VERSION 5.7 ;
  NOWIREEXTENSIONATPIN ON ;
  DIVIDERCHAR "/" ;
  BUSBITCHARS "[]" ;
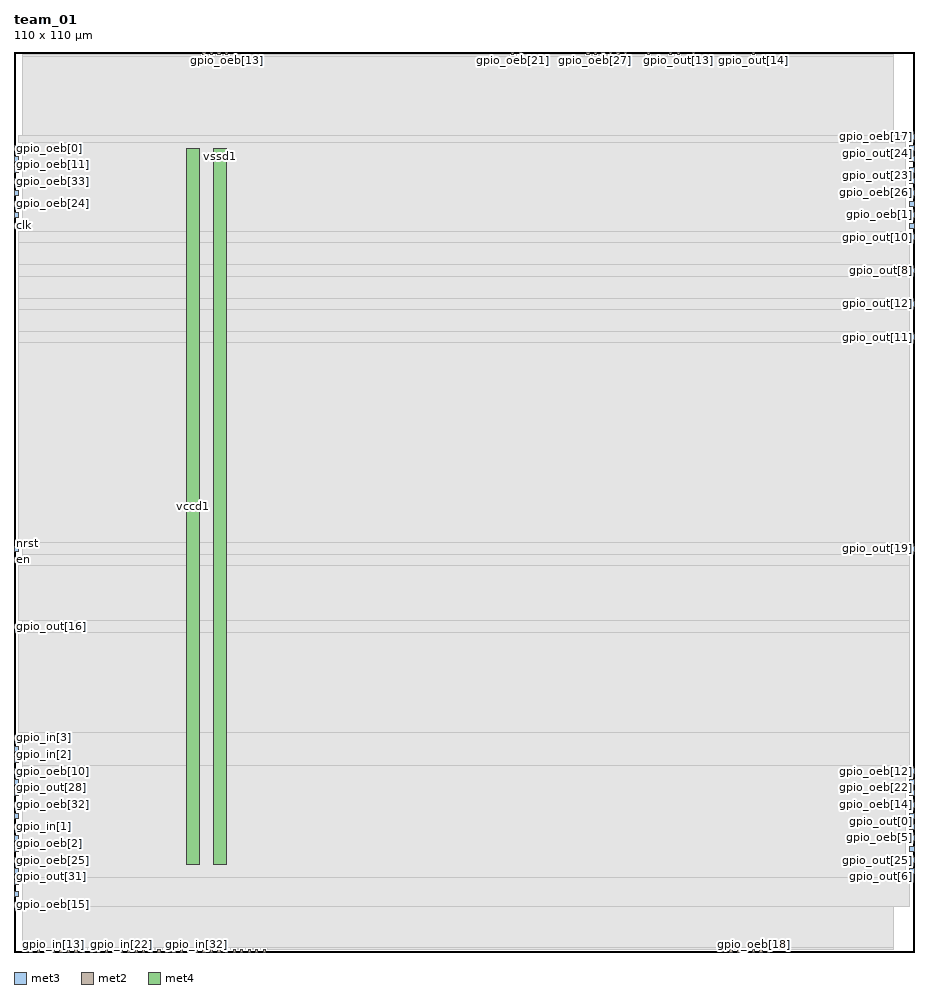
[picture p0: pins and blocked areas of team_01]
MACRO team_01
  CLASS BLOCK ;
  FOREIGN team_01 ;
  ORIGIN 0.000 0.000 ;
  SIZE 110.000 BY 110.000 ;
  PIN clk
    DIRECTION INPUT ;
    USE SIGNAL ;
    ANTENNAGATEAREA 1.286700 ;
    ANTENNADIFFAREA 0.434700 ;
    PORT
      LAYER met3 ;
        RECT 0.000 88.440 0.600 89.040 ;
    END
  END clk
  PIN en
    DIRECTION INPUT ;
    USE SIGNAL ;
    ANTENNAGATEAREA 0.647700 ;
    ANTENNADIFFAREA 0.434700 ;
    PORT
      LAYER met3 ;
        RECT 0.000 47.640 0.600 48.240 ;
    END
  END en
  PIN gpio_in[0]
    DIRECTION INPUT ;
    USE SIGNAL ;
    ANTENNAGATEAREA 0.647700 ;
    ANTENNADIFFAREA 0.434700 ;
    PORT
      LAYER met2 ;
        RECT 23.090 0.000 23.370 0.280 ;
    END
  END gpio_in[0]
  PIN gpio_in[10]
    DIRECTION INPUT ;
    USE SIGNAL ;
    PORT
      LAYER met2 ;
        RECT 1.930 0.000 2.210 0.280 ;
    END
  END gpio_in[10]
  PIN gpio_in[11]
    DIRECTION INPUT ;
    USE SIGNAL ;
    PORT
      LAYER met2 ;
        RECT 2.850 0.000 3.130 0.280 ;
    END
  END gpio_in[11]
  PIN gpio_in[12]
    DIRECTION INPUT ;
    USE SIGNAL ;
    PORT
      LAYER met2 ;
        RECT 3.770 0.000 4.050 0.280 ;
    END
  END gpio_in[12]
  PIN gpio_in[13]
    DIRECTION INPUT ;
    USE SIGNAL ;
    PORT
      LAYER met2 ;
        RECT 4.690 0.000 4.970 0.280 ;
    END
  END gpio_in[13]
  PIN gpio_in[14]
    DIRECTION INPUT ;
    USE SIGNAL ;
    PORT
      LAYER met2 ;
        RECT 5.610 0.000 5.890 0.280 ;
    END
  END gpio_in[14]
  PIN gpio_in[15]
    DIRECTION INPUT ;
    USE SIGNAL ;
    PORT
      LAYER met2 ;
        RECT 6.530 0.000 6.810 0.280 ;
    END
  END gpio_in[15]
  PIN gpio_in[16]
    DIRECTION INPUT ;
    USE SIGNAL ;
    PORT
      LAYER met2 ;
        RECT 7.450 0.000 7.730 0.280 ;
    END
  END gpio_in[16]
  PIN gpio_in[17]
    DIRECTION INPUT ;
    USE SIGNAL ;
    PORT
      LAYER met2 ;
        RECT 8.370 0.000 8.650 0.280 ;
    END
  END gpio_in[17]
  PIN gpio_in[18]
    DIRECTION INPUT ;
    USE SIGNAL ;
    PORT
      LAYER met2 ;
        RECT 9.290 0.000 9.570 0.280 ;
    END
  END gpio_in[18]
  PIN gpio_in[19]
    DIRECTION INPUT ;
    USE SIGNAL ;
    PORT
      LAYER met2 ;
        RECT 10.210 0.000 10.490 0.280 ;
    END
  END gpio_in[19]
  PIN gpio_in[1]
    DIRECTION INPUT ;
    USE SIGNAL ;
    ANTENNAGATEAREA 0.647700 ;
    ANTENNADIFFAREA 0.434700 ;
    PORT
      LAYER met3 ;
        RECT 0.000 15.000 0.600 15.600 ;
    END
  END gpio_in[1]
  PIN gpio_in[20]
    DIRECTION INPUT ;
    USE SIGNAL ;
    PORT
      LAYER met2 ;
        RECT 11.130 0.000 11.410 0.280 ;
    END
  END gpio_in[20]
  PIN gpio_in[21]
    DIRECTION INPUT ;
    USE SIGNAL ;
    PORT
      LAYER met2 ;
        RECT 12.050 0.000 12.330 0.280 ;
    END
  END gpio_in[21]
  PIN gpio_in[22]
    DIRECTION INPUT ;
    USE SIGNAL ;
    PORT
      LAYER met2 ;
        RECT 12.970 0.000 13.250 0.280 ;
    END
  END gpio_in[22]
  PIN gpio_in[23]
    DIRECTION INPUT ;
    USE SIGNAL ;
    PORT
      LAYER met2 ;
        RECT 13.890 0.000 14.170 0.280 ;
    END
  END gpio_in[23]
  PIN gpio_in[24]
    DIRECTION INPUT ;
    USE SIGNAL ;
    PORT
      LAYER met2 ;
        RECT 14.810 0.000 15.090 0.280 ;
    END
  END gpio_in[24]
  PIN gpio_in[25]
    DIRECTION INPUT ;
    USE SIGNAL ;
    PORT
      LAYER met2 ;
        RECT 15.730 0.000 16.010 0.280 ;
    END
  END gpio_in[25]
  PIN gpio_in[26]
    DIRECTION INPUT ;
    USE SIGNAL ;
    PORT
      LAYER met2 ;
        RECT 16.650 0.000 16.930 0.280 ;
    END
  END gpio_in[26]
  PIN gpio_in[27]
    DIRECTION INPUT ;
    USE SIGNAL ;
    PORT
      LAYER met2 ;
        RECT 17.570 0.000 17.850 0.280 ;
    END
  END gpio_in[27]
  PIN gpio_in[28]
    DIRECTION INPUT ;
    USE SIGNAL ;
    PORT
      LAYER met2 ;
        RECT 18.490 0.000 18.770 0.280 ;
    END
  END gpio_in[28]
  PIN gpio_in[29]
    DIRECTION INPUT ;
    USE SIGNAL ;
    PORT
      LAYER met2 ;
        RECT 19.410 0.000 19.690 0.280 ;
    END
  END gpio_in[29]
  PIN gpio_in[2]
    DIRECTION INPUT ;
    USE SIGNAL ;
    ANTENNAGATEAREA 0.647700 ;
    ANTENNADIFFAREA 0.434700 ;
    PORT
      LAYER met3 ;
        RECT 0.000 23.160 0.600 23.760 ;
    END
  END gpio_in[2]
  PIN gpio_in[30]
    DIRECTION INPUT ;
    USE SIGNAL ;
    PORT
      LAYER met2 ;
        RECT 20.330 0.000 20.610 0.280 ;
    END
  END gpio_in[30]
  PIN gpio_in[31]
    DIRECTION INPUT ;
    USE SIGNAL ;
    PORT
      LAYER met2 ;
        RECT 21.250 0.000 21.530 0.280 ;
    END
  END gpio_in[31]
  PIN gpio_in[32]
    DIRECTION INPUT ;
    USE SIGNAL ;
    PORT
      LAYER met2 ;
        RECT 22.170 0.000 22.450 0.280 ;
    END
  END gpio_in[32]
  PIN gpio_in[33]
    DIRECTION INPUT ;
    USE SIGNAL ;
    PORT
      LAYER met2 ;
        RECT 24.010 0.000 24.290 0.280 ;
    END
  END gpio_in[33]
  PIN gpio_in[3]
    DIRECTION INPUT ;
    USE SIGNAL ;
    ANTENNAGATEAREA 0.647700 ;
    ANTENNADIFFAREA 0.434700 ;
    PORT
      LAYER met3 ;
        RECT 0.000 25.880 0.600 26.480 ;
    END
  END gpio_in[3]
  PIN gpio_in[4]
    DIRECTION INPUT ;
    USE SIGNAL ;
    PORT
      LAYER met2 ;
        RECT 24.930 0.000 25.210 0.280 ;
    END
  END gpio_in[4]
  PIN gpio_in[5]
    DIRECTION INPUT ;
    USE SIGNAL ;
    PORT
      LAYER met2 ;
        RECT 25.850 0.000 26.130 0.280 ;
    END
  END gpio_in[5]
  PIN gpio_in[6]
    DIRECTION INPUT ;
    USE SIGNAL ;
    PORT
      LAYER met2 ;
        RECT 26.770 0.000 27.050 0.280 ;
    END
  END gpio_in[6]
  PIN gpio_in[7]
    DIRECTION INPUT ;
    USE SIGNAL ;
    PORT
      LAYER met2 ;
        RECT 27.690 0.000 27.970 0.280 ;
    END
  END gpio_in[7]
  PIN gpio_in[8]
    DIRECTION INPUT ;
    USE SIGNAL ;
    PORT
      LAYER met2 ;
        RECT 28.610 0.000 28.890 0.280 ;
    END
  END gpio_in[8]
  PIN gpio_in[9]
    DIRECTION INPUT ;
    USE SIGNAL ;
    PORT
      LAYER met2 ;
        RECT 29.530 0.000 29.810 0.280 ;
    END
  END gpio_in[9]
  PIN gpio_oeb[0]
    DIRECTION OUTPUT ;
    USE SIGNAL ;
    PORT
      LAYER met3 ;
        RECT 0.000 97.960 0.600 98.560 ;
    END
  END gpio_oeb[0]
  PIN gpio_oeb[10]
    DIRECTION OUTPUT ;
    USE SIGNAL ;
    PORT
      LAYER met3 ;
        RECT 0.000 21.800 0.600 22.400 ;
    END
  END gpio_oeb[10]
  PIN gpio_oeb[11]
    DIRECTION OUTPUT ;
    USE SIGNAL ;
    PORT
      LAYER met3 ;
        RECT 0.000 96.600 0.600 97.200 ;
    END
  END gpio_oeb[11]
  PIN gpio_oeb[12]
    DIRECTION OUTPUT ;
    USE SIGNAL ;
    PORT
      LAYER met3 ;
        RECT 109.400 21.800 110.000 22.400 ;
    END
  END gpio_oeb[12]
  PIN gpio_oeb[13]
    DIRECTION OUTPUT ;
    USE SIGNAL ;
    PORT
      LAYER met2 ;
        RECT 25.850 109.720 26.130 110.000 ;
    END
  END gpio_oeb[13]
  PIN gpio_oeb[14]
    DIRECTION OUTPUT ;
    USE SIGNAL ;
    PORT
      LAYER met3 ;
        RECT 109.400 17.720 110.000 18.320 ;
    END
  END gpio_oeb[14]
  PIN gpio_oeb[15]
    DIRECTION OUTPUT ;
    USE SIGNAL ;
    PORT
      LAYER met3 ;
        RECT 0.000 5.480 0.600 6.080 ;
    END
  END gpio_oeb[15]
  PIN gpio_oeb[16]
    DIRECTION OUTPUT ;
    USE SIGNAL ;
    PORT
      LAYER met2 ;
        RECT 70.010 109.720 70.290 110.000 ;
    END
  END gpio_oeb[16]
  PIN gpio_oeb[17]
    DIRECTION OUTPUT ;
    USE SIGNAL ;
    PORT
      LAYER met3 ;
        RECT 109.400 99.320 110.000 99.920 ;
    END
  END gpio_oeb[17]
  PIN gpio_oeb[18]
    DIRECTION OUTPUT ;
    USE SIGNAL ;
    PORT
      LAYER met2 ;
        RECT 90.250 0.000 90.530 0.280 ;
    END
  END gpio_oeb[18]
  PIN gpio_oeb[19]
    DIRECTION OUTPUT ;
    USE SIGNAL ;
    PORT
      LAYER met2 ;
        RECT 87.490 0.000 87.770 0.280 ;
    END
  END gpio_oeb[19]
  PIN gpio_oeb[1]
    DIRECTION OUTPUT ;
    USE SIGNAL ;
    PORT
      LAYER met3 ;
        RECT 109.400 89.800 110.000 90.400 ;
    END
  END gpio_oeb[1]
  PIN gpio_oeb[20]
    DIRECTION OUTPUT ;
    USE SIGNAL ;
    PORT
      LAYER met2 ;
        RECT 72.770 109.720 73.050 110.000 ;
    END
  END gpio_oeb[20]
  PIN gpio_oeb[21]
    DIRECTION OUTPUT ;
    USE SIGNAL ;
    PORT
      LAYER met2 ;
        RECT 60.810 109.720 61.090 110.000 ;
    END
  END gpio_oeb[21]
  PIN gpio_oeb[22]
    DIRECTION OUTPUT ;
    USE SIGNAL ;
    PORT
      LAYER met3 ;
        RECT 109.400 20.440 110.000 21.040 ;
    END
  END gpio_oeb[22]
  PIN gpio_oeb[23]
    DIRECTION OUTPUT ;
    USE SIGNAL ;
    PORT
      LAYER met2 ;
        RECT 73.690 109.720 73.970 110.000 ;
    END
  END gpio_oeb[23]
  PIN gpio_oeb[24]
    DIRECTION OUTPUT ;
    USE SIGNAL ;
    PORT
      LAYER met3 ;
        RECT 0.000 91.160 0.600 91.760 ;
    END
  END gpio_oeb[24]
  PIN gpio_oeb[25]
    DIRECTION OUTPUT ;
    USE SIGNAL ;
    PORT
      LAYER met3 ;
        RECT 0.000 10.920 0.600 11.520 ;
    END
  END gpio_oeb[25]
  PIN gpio_oeb[26]
    DIRECTION OUTPUT ;
    USE SIGNAL ;
    PORT
      LAYER met3 ;
        RECT 109.400 92.520 110.000 93.120 ;
    END
  END gpio_oeb[26]
  PIN gpio_oeb[27]
    DIRECTION OUTPUT ;
    USE SIGNAL ;
    PORT
      LAYER met2 ;
        RECT 70.930 109.720 71.210 110.000 ;
    END
  END gpio_oeb[27]
  PIN gpio_oeb[28]
    DIRECTION OUTPUT ;
    USE SIGNAL ;
    PORT
      LAYER met3 ;
        RECT 109.400 12.280 110.000 12.880 ;
    END
  END gpio_oeb[28]
  PIN gpio_oeb[29]
    DIRECTION OUTPUT ;
    USE SIGNAL ;
    PORT
      LAYER met2 ;
        RECT 23.090 109.720 23.370 110.000 ;
    END
  END gpio_oeb[29]
  PIN gpio_oeb[2]
    DIRECTION OUTPUT ;
    USE SIGNAL ;
    PORT
      LAYER met3 ;
        RECT 0.000 13.640 0.600 14.240 ;
    END
  END gpio_oeb[2]
  PIN gpio_oeb[30]
    DIRECTION OUTPUT ;
    USE SIGNAL ;
    PORT
      LAYER met3 ;
        RECT 109.400 91.160 110.000 91.760 ;
    END
  END gpio_oeb[30]
  PIN gpio_oeb[31]
    DIRECTION OUTPUT ;
    USE SIGNAL ;
    PORT
      LAYER met3 ;
        RECT 0.000 12.280 0.600 12.880 ;
    END
  END gpio_oeb[31]
  PIN gpio_oeb[32]
    DIRECTION OUTPUT ;
    USE SIGNAL ;
    PORT
      LAYER met3 ;
        RECT 0.000 17.720 0.600 18.320 ;
    END
  END gpio_oeb[32]
  PIN gpio_oeb[33]
    DIRECTION OUTPUT ;
    USE SIGNAL ;
    PORT
      LAYER met3 ;
        RECT 0.000 93.880 0.600 94.480 ;
    END
  END gpio_oeb[33]
  PIN gpio_oeb[3]
    DIRECTION OUTPUT ;
    USE SIGNAL ;
    PORT
      LAYER met3 ;
        RECT 0.000 24.520 0.600 25.120 ;
    END
  END gpio_oeb[3]
  PIN gpio_oeb[4]
    DIRECTION OUTPUT ;
    USE SIGNAL ;
    PORT
      LAYER met3 ;
        RECT 0.000 92.520 0.600 93.120 ;
    END
  END gpio_oeb[4]
  PIN gpio_oeb[5]
    DIRECTION OUTPUT ;
    USE SIGNAL ;
    PORT
      LAYER met3 ;
        RECT 109.400 13.640 110.000 14.240 ;
    END
  END gpio_oeb[5]
  PIN gpio_oeb[6]
    DIRECTION OUTPUT ;
    USE SIGNAL ;
    PORT
      LAYER met2 ;
        RECT 88.410 0.000 88.690 0.280 ;
    END
  END gpio_oeb[6]
  PIN gpio_oeb[7]
    DIRECTION OUTPUT ;
    USE SIGNAL ;
    PORT
      LAYER met3 ;
        RECT 0.000 89.800 0.600 90.400 ;
    END
  END gpio_oeb[7]
  PIN gpio_oeb[8]
    DIRECTION OUTPUT ;
    USE SIGNAL ;
    PORT
      LAYER met3 ;
        RECT 0.000 8.200 0.600 8.800 ;
    END
  END gpio_oeb[8]
  PIN gpio_oeb[9]
    DIRECTION OUTPUT ;
    USE SIGNAL ;
    PORT
      LAYER met2 ;
        RECT 24.930 109.720 25.210 110.000 ;
    END
  END gpio_oeb[9]
  PIN gpio_out[0]
    DIRECTION OUTPUT ;
    USE SIGNAL ;
    PORT
      LAYER met3 ;
        RECT 109.400 15.000 110.000 15.600 ;
    END
  END gpio_out[0]
  PIN gpio_out[10]
    DIRECTION OUTPUT ;
    USE SIGNAL ;
    ANTENNADIFFAREA 0.702900 ;
    PORT
      LAYER met3 ;
        RECT 109.400 87.080 110.000 87.680 ;
    END
  END gpio_out[10]
  PIN gpio_out[11]
    DIRECTION OUTPUT ;
    USE SIGNAL ;
    ANTENNADIFFAREA 0.702900 ;
    PORT
      LAYER met3 ;
        RECT 109.400 74.840 110.000 75.440 ;
    END
  END gpio_out[11]
  PIN gpio_out[12]
    DIRECTION OUTPUT ;
    USE SIGNAL ;
    ANTENNADIFFAREA 0.702900 ;
    PORT
      LAYER met3 ;
        RECT 109.400 78.920 110.000 79.520 ;
    END
  END gpio_out[12]
  PIN gpio_out[13]
    DIRECTION OUTPUT ;
    USE SIGNAL ;
    ANTENNADIFFAREA 0.702900 ;
    PORT
      LAYER met2 ;
        RECT 81.050 109.720 81.330 110.000 ;
    END
  END gpio_out[13]
  PIN gpio_out[14]
    DIRECTION OUTPUT ;
    USE SIGNAL ;
    ANTENNADIFFAREA 0.702900 ;
    PORT
      LAYER met2 ;
        RECT 90.250 109.720 90.530 110.000 ;
    END
  END gpio_out[14]
  PIN gpio_out[15]
    DIRECTION OUTPUT ;
    USE SIGNAL ;
    PORT
      LAYER met2 ;
        RECT 92.090 0.000 92.370 0.280 ;
    END
  END gpio_out[15]
  PIN gpio_out[16]
    DIRECTION OUTPUT ;
    USE SIGNAL ;
    ANTENNADIFFAREA 0.702900 ;
    PORT
      LAYER met3 ;
        RECT 0.000 39.480 0.600 40.080 ;
    END
  END gpio_out[16]
  PIN gpio_out[17]
    DIRECTION OUTPUT ;
    USE SIGNAL ;
    ANTENNADIFFAREA 0.702900 ;
    PORT
      LAYER met2 ;
        RECT 30.450 0.000 30.730 0.280 ;
    END
  END gpio_out[17]
  PIN gpio_out[18]
    DIRECTION OUTPUT ;
    USE SIGNAL ;
    ANTENNADIFFAREA 0.702900 ;
    PORT
      LAYER met2 ;
        RECT 77.370 109.720 77.650 110.000 ;
    END
  END gpio_out[18]
  PIN gpio_out[19]
    DIRECTION OUTPUT ;
    USE SIGNAL ;
    ANTENNADIFFAREA 0.702900 ;
    PORT
      LAYER met3 ;
        RECT 109.400 49.000 110.000 49.600 ;
    END
  END gpio_out[19]
  PIN gpio_out[1]
    DIRECTION OUTPUT ;
    USE SIGNAL ;
    PORT
      LAYER met2 ;
        RECT 24.010 109.720 24.290 110.000 ;
    END
  END gpio_out[1]
  PIN gpio_out[20]
    DIRECTION OUTPUT ;
    USE SIGNAL ;
    ANTENNADIFFAREA 0.702900 ;
    PORT
      LAYER met2 ;
        RECT 80.130 109.720 80.410 110.000 ;
    END
  END gpio_out[20]
  PIN gpio_out[21]
    DIRECTION OUTPUT ;
    USE SIGNAL ;
    PORT
      LAYER met3 ;
        RECT 109.400 16.360 110.000 16.960 ;
    END
  END gpio_out[21]
  PIN gpio_out[22]
    DIRECTION OUTPUT ;
    USE SIGNAL ;
    PORT
      LAYER met3 ;
        RECT 109.400 19.080 110.000 19.680 ;
    END
  END gpio_out[22]
  PIN gpio_out[23]
    DIRECTION OUTPUT ;
    USE SIGNAL ;
    PORT
      LAYER met3 ;
        RECT 109.400 93.880 110.000 94.480 ;
    END
  END gpio_out[23]
  PIN gpio_out[24]
    DIRECTION OUTPUT ;
    USE SIGNAL ;
    PORT
      LAYER met3 ;
        RECT 109.400 97.960 110.000 98.560 ;
    END
  END gpio_out[24]
  PIN gpio_out[25]
    DIRECTION OUTPUT ;
    USE SIGNAL ;
    PORT
      LAYER met3 ;
        RECT 109.400 10.920 110.000 11.520 ;
    END
  END gpio_out[25]
  PIN gpio_out[26]
    DIRECTION OUTPUT ;
    USE SIGNAL ;
    PORT
      LAYER met3 ;
        RECT 0.000 16.360 0.600 16.960 ;
    END
  END gpio_out[26]
  PIN gpio_out[27]
    DIRECTION OUTPUT ;
    USE SIGNAL ;
    PORT
      LAYER met3 ;
        RECT 109.400 88.440 110.000 89.040 ;
    END
  END gpio_out[27]
  PIN gpio_out[28]
    DIRECTION OUTPUT ;
    USE SIGNAL ;
    PORT
      LAYER met3 ;
        RECT 0.000 20.440 0.600 21.040 ;
    END
  END gpio_out[28]
  PIN gpio_out[29]
    DIRECTION OUTPUT ;
    USE SIGNAL ;
    PORT
      LAYER met3 ;
        RECT 0.000 6.840 0.600 7.440 ;
    END
  END gpio_out[29]
  PIN gpio_out[2]
    DIRECTION OUTPUT ;
    USE SIGNAL ;
    PORT
      LAYER met3 ;
        RECT 109.400 95.240 110.000 95.840 ;
    END
  END gpio_out[2]
  PIN gpio_out[30]
    DIRECTION OUTPUT ;
    USE SIGNAL ;
    PORT
      LAYER met2 ;
        RECT 61.730 109.720 62.010 110.000 ;
    END
  END gpio_out[30]
  PIN gpio_out[31]
    DIRECTION OUTPUT ;
    USE SIGNAL ;
    PORT
      LAYER met3 ;
        RECT 0.000 9.560 0.600 10.160 ;
    END
  END gpio_out[31]
  PIN gpio_out[32]
    DIRECTION OUTPUT ;
    USE SIGNAL ;
    PORT
      LAYER met3 ;
        RECT 0.000 19.080 0.600 19.680 ;
    END
  END gpio_out[32]
  PIN gpio_out[33]
    DIRECTION OUTPUT ;
    USE SIGNAL ;
    PORT
      LAYER met2 ;
        RECT 74.610 109.720 74.890 110.000 ;
    END
  END gpio_out[33]
  PIN gpio_out[3]
    DIRECTION OUTPUT ;
    USE SIGNAL ;
    PORT
      LAYER met3 ;
        RECT 109.400 96.600 110.000 97.200 ;
    END
  END gpio_out[3]
  PIN gpio_out[4]
    DIRECTION OUTPUT ;
    USE SIGNAL ;
    PORT
      LAYER met2 ;
        RECT 91.170 0.000 91.450 0.280 ;
    END
  END gpio_out[4]
  PIN gpio_out[5]
    DIRECTION OUTPUT ;
    USE SIGNAL ;
    PORT
      LAYER met3 ;
        RECT 0.000 95.240 0.600 95.840 ;
    END
  END gpio_out[5]
  PIN gpio_out[6]
    DIRECTION OUTPUT ;
    USE SIGNAL ;
    PORT
      LAYER met3 ;
        RECT 109.400 9.560 110.000 10.160 ;
    END
  END gpio_out[6]
  PIN gpio_out[7]
    DIRECTION OUTPUT ;
    USE SIGNAL ;
    PORT
      LAYER met2 ;
        RECT 71.850 109.720 72.130 110.000 ;
    END
  END gpio_out[7]
  PIN gpio_out[8]
    DIRECTION OUTPUT ;
    USE SIGNAL ;
    ANTENNADIFFAREA 0.702900 ;
    PORT
      LAYER met3 ;
        RECT 109.400 83.000 110.000 83.600 ;
    END
  END gpio_out[8]
  PIN gpio_out[9]
    DIRECTION OUTPUT ;
    USE SIGNAL ;
    ANTENNADIFFAREA 0.702900 ;
    PORT
      LAYER met2 ;
        RECT 82.890 109.720 83.170 110.000 ;
    END
  END gpio_out[9]
  PIN nrst
    DIRECTION INPUT ;
    USE SIGNAL ;
    ANTENNAGATEAREA 0.647700 ;
    ANTENNADIFFAREA 0.434700 ;
    PORT
      LAYER met3 ;
        RECT 0.000 49.000 0.600 49.600 ;
    END
  END nrst
  PIN vccd1
    DIRECTION INOUT ;
    USE POWER ;
    PORT
      LAYER met4 ;
        RECT 21.040 10.640 22.640 98.160 ;
    END
  END vccd1
  PIN vssd1
    DIRECTION INOUT ;
    USE GROUND ;
    PORT
      LAYER met4 ;
        RECT 24.340 10.640 25.940 98.160 ;
    END
  END vssd1
  OBS
      LAYER nwell ;
        RECT 5.330 10.760 104.610 98.040 ;
      LAYER li1 ;
        RECT 5.520 10.795 104.420 98.005 ;
      LAYER met1 ;
        RECT 0.990 10.640 107.570 98.160 ;
      LAYER met2 ;
        RECT 1.010 109.440 22.810 109.720 ;
        RECT 23.650 109.440 23.730 109.720 ;
        RECT 24.570 109.440 24.650 109.720 ;
        RECT 25.490 109.440 25.570 109.720 ;
        RECT 26.410 109.440 60.530 109.720 ;
        RECT 61.370 109.440 61.450 109.720 ;
        RECT 62.290 109.440 69.730 109.720 ;
        RECT 70.570 109.440 70.650 109.720 ;
        RECT 71.490 109.440 71.570 109.720 ;
        RECT 72.410 109.440 72.490 109.720 ;
        RECT 73.330 109.440 73.410 109.720 ;
        RECT 74.250 109.440 74.330 109.720 ;
        RECT 75.170 109.440 77.090 109.720 ;
        RECT 77.930 109.440 79.850 109.720 ;
        RECT 80.690 109.440 80.770 109.720 ;
        RECT 81.610 109.440 82.610 109.720 ;
        RECT 83.450 109.440 89.970 109.720 ;
        RECT 90.810 109.440 107.550 109.720 ;
        RECT 1.010 0.560 107.550 109.440 ;
        RECT 1.010 0.280 1.650 0.560 ;
        RECT 2.490 0.280 2.570 0.560 ;
        RECT 3.410 0.280 3.490 0.560 ;
        RECT 4.330 0.280 4.410 0.560 ;
        RECT 5.250 0.280 5.330 0.560 ;
        RECT 6.170 0.280 6.250 0.560 ;
        RECT 7.090 0.280 7.170 0.560 ;
        RECT 8.010 0.280 8.090 0.560 ;
        RECT 8.930 0.280 9.010 0.560 ;
        RECT 9.850 0.280 9.930 0.560 ;
        RECT 10.770 0.280 10.850 0.560 ;
        RECT 11.690 0.280 11.770 0.560 ;
        RECT 12.610 0.280 12.690 0.560 ;
        RECT 13.530 0.280 13.610 0.560 ;
        RECT 14.450 0.280 14.530 0.560 ;
        RECT 15.370 0.280 15.450 0.560 ;
        RECT 16.290 0.280 16.370 0.560 ;
        RECT 17.210 0.280 17.290 0.560 ;
        RECT 18.130 0.280 18.210 0.560 ;
        RECT 19.050 0.280 19.130 0.560 ;
        RECT 19.970 0.280 20.050 0.560 ;
        RECT 20.890 0.280 20.970 0.560 ;
        RECT 21.810 0.280 21.890 0.560 ;
        RECT 22.730 0.280 22.810 0.560 ;
        RECT 23.650 0.280 23.730 0.560 ;
        RECT 24.570 0.280 24.650 0.560 ;
        RECT 25.490 0.280 25.570 0.560 ;
        RECT 26.410 0.280 26.490 0.560 ;
        RECT 27.330 0.280 27.410 0.560 ;
        RECT 28.250 0.280 28.330 0.560 ;
        RECT 29.170 0.280 29.250 0.560 ;
        RECT 30.090 0.280 30.170 0.560 ;
        RECT 31.010 0.280 87.210 0.560 ;
        RECT 88.050 0.280 88.130 0.560 ;
        RECT 88.970 0.280 89.970 0.560 ;
        RECT 90.810 0.280 90.890 0.560 ;
        RECT 91.730 0.280 91.810 0.560 ;
        RECT 92.650 0.280 107.550 0.560 ;
      LAYER met3 ;
        RECT 0.600 98.960 109.000 99.785 ;
        RECT 1.000 88.040 109.000 98.960 ;
        RECT 0.600 86.680 109.000 88.040 ;
        RECT 0.600 84.000 109.400 86.680 ;
        RECT 0.600 82.600 109.000 84.000 ;
        RECT 0.600 79.920 109.400 82.600 ;
        RECT 0.600 78.520 109.000 79.920 ;
        RECT 0.600 75.840 109.400 78.520 ;
        RECT 0.600 74.440 109.000 75.840 ;
        RECT 0.600 50.000 109.400 74.440 ;
        RECT 1.000 48.600 109.000 50.000 ;
        RECT 1.000 47.240 109.400 48.600 ;
        RECT 0.600 40.480 109.400 47.240 ;
        RECT 1.000 39.080 109.400 40.480 ;
        RECT 0.600 26.880 109.400 39.080 ;
        RECT 1.000 22.800 109.400 26.880 ;
        RECT 1.000 9.160 109.000 22.800 ;
        RECT 1.000 5.615 109.400 9.160 ;
  END
END team_01
END LIBRARY

